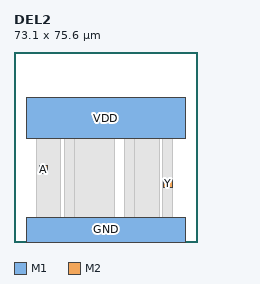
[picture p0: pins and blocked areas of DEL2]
MACRO DEL2
  CLASS CORE ;
  ORIGIN 0 0 ;
  SIZE 73.100 BY 75.600 ;
  SYMMETRY X Y ;
  SITE TR1um_access_site ;
  PIN VDD
    DIRECTION INOUT ;
    USE POWER ;
    PORT
      LAYER M1 ;
        RECT 5.000 41.000 68.100 57.600 ;
    END
  END VDD
  PIN GND
    DIRECTION INOUT ;
    USE GROUND ;
    PORT
      LAYER M1 ;
        RECT 5.000 0.000 68.100 9.800 ;
    END
  END GND
  PIN A
    DIRECTION INPUT ;
    USE SIGNAL ;
    PORT
      LAYER M2 ;
        RECT 10.100 27.100 13.500 30.500 ;
    END
  END A
  PIN Y
    DIRECTION OUTPUT ;
    USE SIGNAL ;
    PORT
      LAYER M2 ;
        RECT 59.600 21.600 63.000 25.000 ;
    END
  END Y
  OBS
    LAYER M1 ;
      RECT 10.100 22.000 14.500 30.500 ;
    LAYER M1 ;
      RECT 9.100 6.400 18.600 51.200 ;
    LAYER M1 ;
      RECT 20.100 6.400 29.900 51.200 ;
    LAYER M1 ;
      RECT 24.100 6.400 39.900 51.200 ;
    LAYER M1 ;
      RECT 44.100 6.400 52.600 51.200 ;
    LAYER M1 ;
      RECT 48.100 6.400 57.800 51.200 ;
    LAYER M1 ;
      RECT 59.100 6.400 63.000 51.200 ;
    LAYER V1 ;
      RECT 60.600 22.600 62.000 24.000 ;
    LAYER V1 ;
      RECT 11.100 28.100 12.500 29.500 ;
  END
END DEL2
